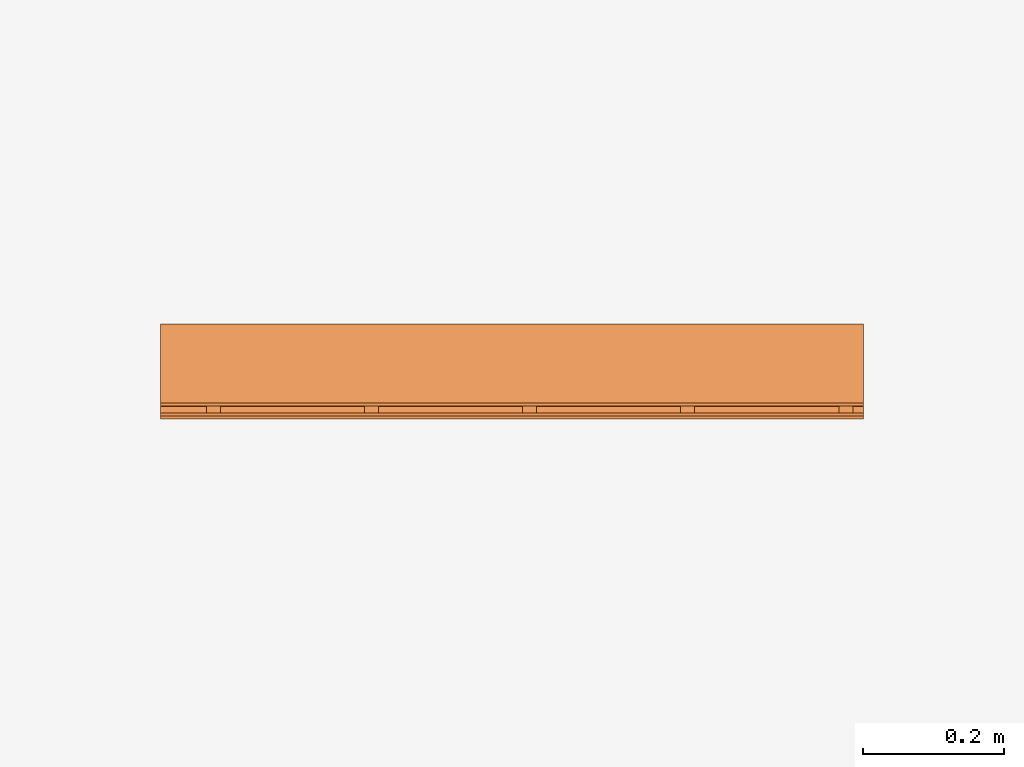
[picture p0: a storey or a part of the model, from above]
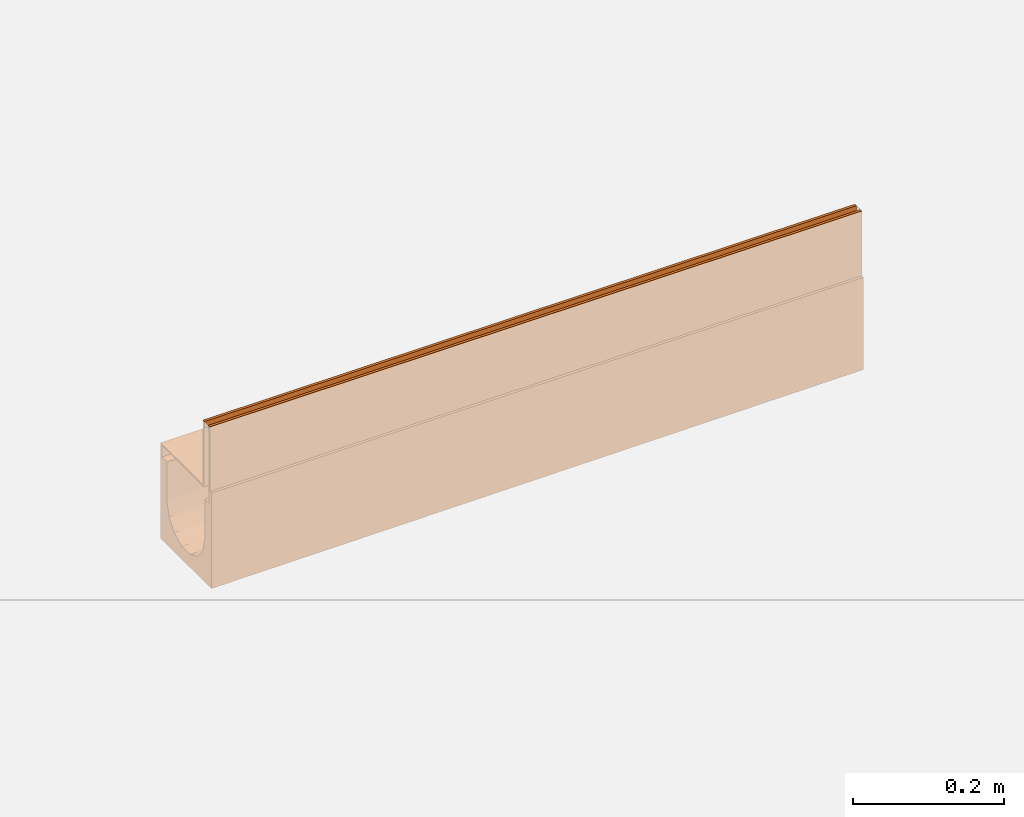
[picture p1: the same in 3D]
Properties of the parts of a building model (IFC2X3)

# File
Description: ViewDefinition [CoordinationView]
File name: 23001 - No 1 Sloping Channel - 1000mm LG - Invert Depth 130-135mm.ifc
Time: 2013-10-31T17:19:47
Written by: Autodesk Revit 2013
Made in: 20120221_2030(x64)

# IfcProject, Project Number
LongName: Project Name; Phase: Project Status

# IfcSite, Default
RefLatitude: 42, 21, 30, 344238; RefLongitude: -71, -3, -35, -194702; RefElevation: 0 mm

# IfcBuilding
Pset_BuildingCommon - NumberOfStoreys: 1
Other - Project Status: Project Status; Client Name: Owner; Project Address: ## Street City, State Zip; Project Issue Date: Issue Date; Project Number: Project Number; Project Name: Project Name

# IfcBuildingStorey, Level 1
LongName: Level 1; Elevation: 0 mm
Constraints - Elevation Base: 0; Elevation: 0 mm
Graphics - Symbol at End 2 Default: yes; Symbol: M_Level Head - Circle: M_Level Head - Circle; Line Pattern: Center; Color: 0; Symbol at End 1 Default: no; Line Weight: 1
Identity Data - Name: Level 1; Structural: no; Building Story: yes
Dimensions - Computation Height: 0 mm

# IfcBuildingElementProxy: 23001 - No 1 Sloping Channel - 1000mm LG - Invert Depth 130/135mm, Civil-Drainage-Channel-ACO-MultiDrain-M100D-Brickslot-Channel-System:23001 - No 1 Sloping Channel - 1000mm LG - Invert Depth 130/135mm:23001 - No 1 Sloping Channel - 1000mm LG - Invert Depth 130/135mm:196059
In: Level 1
Material: Steel, Galvanized, Vienite® Synthetic Resin Concrete
Construction - 23460_Load Class C250_Brickslot Grating_Galvanized Steel_1000mm Long: no; 23461_Load Class C250_Brickslot Grating_Galvanized Steel_500mm Long: no; 23465_Load Class D400_Brickslot Grating_Galvanized Steel_1000mm Long: yes; 23466_Load Class D400_Brickslot Grating_Galvanized Steel_500mm Long: no; 23404_Universal Endcap (Male End): no; 23467_Load Class D400_Brickslot Access Unit_Galvanised Steel_500mm Long: no; 23462_Load Class C250_Brickslot Access Unit_Galvanised Steel_500mm Long: no; 23404_Universal Endcap (Female End): no; Shallow Depth Channel with seal: no; 23410_Sump Unit: no; Sloping Channel: yes; Constant Depth Channel: no; Shallow Depth Channel: no; Constant Depth Junction Channel: no
Dimensions - Brickslot Void Length: 1000 mm; Volume: 8676328 mm3; FloorCut_Length: -1000 mm; Length: 1000 mm; Brickslot Access Unit Void Bottom Depth: -6605 mm; EndCap Position: 1000 mm; Brickslot Access Unit Void Depth: -6500 mm; Custom_Void_length: 0 mm; Brickslot Void Depth: 0 mm; InvDepth: 80 mm; FloorCut_Width: 135 mm; FloorCut_Depth: 155 mm; SlopingInvertDepth: 80 mm; SlopingEndOverallDepth: 155 mm; ShallowOverallDepth: 75 mm; Length Drain: -1000 mm; Depth: 150 mm; Access_Custom_Void_Length: 0 mm; SlopingEndInvertDepth: 85 mm; ShallowInvDepth: 55 mm; EndCap_Height: 155 mm; GratingLength: -1000 mm; Brickslot Access Unit Floor Cut Length: 500 mm; SlopingOverallDepth: 150 mm; Floor Cut Gap: 105 mm
Phasing - Phase Created: New Construction
Constraints - Level: Level: Level 1; Moves With Nearby Elements: no
Pset_BuildingElementProxyCommon - Reference: 23001 - No 1 Sloping Channel - 1000mm LG - Invert Depth 130/135mm
Materials and Finishes - Edge Rail Material: Steel; Edge Rail Finish: Pre-galvanised; Channel Colour: Brown; Channel Material: Vienite® Synthetic Resin Concrete; Edge Rail Colour: Silver
Identity Data - Watermarked With: BIM Manager Premium Suite; Maintenance guidelines: http://www.aco.co.uk/download.php?id=173; Address: ACO Business Park, Hitchin Road, Shefford, Bedfordshire, United Kingdom SG17 5TE; Watermark 2: This file is water marked and users are prohibited to reproduce, adapt, distribute this information; Manufacturer: ACO Technologies PLC - ACO Water Management Division; Assembly Code: D2040; e-mail Technical: technical@aco.co.uk; Model Description: Channel drainage system; Model: ACO MultiDrain MD Brickslot- M100D; Telephone: +44 (0)1462 816666; OmniClass Title: Rainwater Removal; Assembly Description: Rain Water Drainage; Cost: 0; URL: www.aco.co.uk; Installation guidelines: http://www.aco.co.uk/download.php?id=173; Product brochure: http://www.aco.co.uk/download.php?id=173; e-mail Sales: customersupport@aco.co.uk; Type Comments: ACO MultiDrain M100D No 1 Sloping Channel 1000mm Long; Product Page URL: http://www.aco.co.uk/product_detail.php?id=58; Price: POA - Contact ACO; Watermark 1: This file is the property of ACO Technologies PLC; OmniClass Number: 23.70.50.24; Product Code: 23001; Fax: +44 (0)1462 815895
General - SerialNumber: 0; TagNumber: 0
Data - Product Dimensions: 1000mm x 135mm x 150mm/155mm (LxWxH); Product Weight: 13.5 Kg; Pre-formed Outlet Ø: N/A; Load Class: A 15 - D 400; Concrete Surround Volume - Load Class B 125 - C 250 - Concrete Pavement: N/A; Hydraulic Performance: http://www.aco.co.uk/download.php?id=173; Product Standard: BS EN 1433:2002, CE marked; Concrete Surround Volume - Load Class A 15 - Concrete Pavement: N/A; Concrete Surround Volume - Load Class D 400 - Concrete Pavement: N/A; ACO Hydraulic Design Software: http://www.acodesign.co.uk; Invert Depth: 130mm/135mm; Installation - Concrete Grade: Refer to brochure; Channel C.S.A: N/A
Green Building Properties - Channel Recycled Material Content: 20% minimum; Edge Rail Recyclable: Fully recyclable; Edge Rail Recycled Material Content: Between 40% - 90%; Channel Recyclable: Fully recyclable
Other - Watermarked By: www.aco.co.uk; Revision: 1; Created By: www.aco.co.uk
Model Properties - End Cap Product code 23404: No 306 Universal End Cap - 135mm wide x 300mm long - Spigot Ø110mm x 50mm long - Silver - Polypropylene - 0.16kg; Brickslot Access Unit Product code 23467: Load Class D400 - Brickslot Access Unit Galvanised Steel - 500mm long x 105mm high - 10mm Slot - Intake area - 10000mm²/m - 6.4 Kg; Brickslot Grating Product code 23460: Load Class C250 - Brickslot Galvanised Steel - 1000mm long x 105mm high - 10mm Slot - Intake area - 10000mm²/m - 6.6 Kg; Brickslot Grating Product code 23466: Load Class D400 - Brickslot Galvanised Steel - 500mm long x 105mm high - 10mm Slot - Intake area - 10000mm²/m - 3.3 Kg; Brickslot Grating Product code 23465: Load Class D400 - Brickslot Galvanised Steel - 1000mm long x 105mm high - 10mm Slot - Intake area - 10000mm²/m - 6.6 Kg; Brickslot Grating Product code 23461: Load Class C250 - Brickslot Galvanised Steel - 500mm long x 105mm high - 10mm Slot - Intake area - 10000mm²/m -3.3 Kg; Brickslot Access Unit Product code 23462: Load Class C250 - Brickslot Access Unit Galvanised Steel - 500mm long x 105mm high - 10mm Slot - Intake area - 10000mm²/m - 6.4 Kg

# IfcOpeningElement: Recess (2)
In: Level 1
Constraints - Height Offset From Level: 0 mm; Related to Mass: no; Level: Level: Level 1; Room Bounding: yes
Dimensions - Perimeter: 20000 mm; Volume: 24977185000 mm3; Area: 25000000 mm2; Thickness: 1000 mm
Phasing - Phase Created: New Construction
Structural - Structural: no; Enable Analytical Model: no
Construction - Default Thickness: 1000 mm; Function: 0
Graphics - Coarse Scale Fill Color: 0
Analytical Properties - Heat Transfer Coefficient (U): 0.837; Thermal Resistance (R): 1.19474; Thermal mass: 1359800; Absorptance: 0.1; Roughness: 1
Materials and Finishes - Structural Material: Earth

# IfcSlab: Floor:Generic Floor - 1000mm, Floor:Generic Floor - 1000mm:193825
In: Level 1
PredefinedType: FLOOR; Material: Earth 1000 mm
Constraints - Height Offset From Level: 0 mm; Related to Mass: no; Level: Level: Level 1; Room Bounding: yes
Dimensions - Perimeter: 20000 mm; Volume: 24977185000 mm3; Area: 25000000 mm2; Thickness: 1000 mm
Phasing - Phase Created: New Construction
Structural - Structural: no; Enable Analytical Model: no
Pset_SlabCommon - Reference: Generic Floor - 1000mm; IsExternal: no; LoadBearing: yes
Construction - Default Thickness: 1000 mm; Function: 0
Graphics - Coarse Scale Fill Color: 0
Analytical Properties - Heat Transfer Coefficient (U): 0.837; Thermal Resistance (R): 1.19474; Thermal mass: 1359800; Absorptance: 0.1; Roughness: 1
Materials and Finishes - Structural Material: Earth
